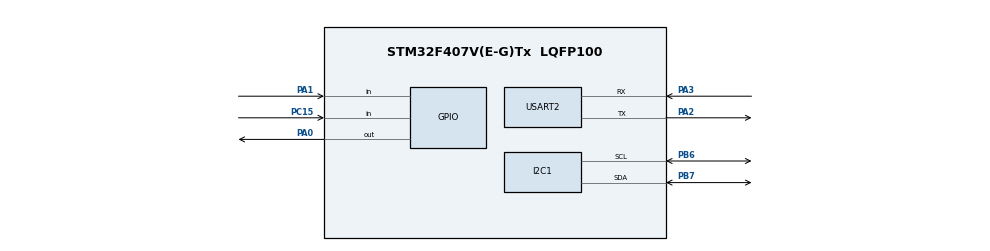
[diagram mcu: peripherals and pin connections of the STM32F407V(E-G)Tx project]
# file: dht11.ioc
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I2C1.I2C_Mode=I2C_Standard
Mcu.Family=STM32F4
Mcu.Name=STM32F407V(E-G)Tx
Mcu.Package=LQFP100
NVIC.PriorityGroup=NVIC_PRIORITYGROUP_4
PA0-WKUP.Signal=GPIO_Output
PA1.Signal=GPIO_Input
PA13.Mode=Serial_Wire
PA13.Signal=SYS_JTMS-SWDIO
PA14.Mode=Serial_Wire
PA14.Signal=SYS_JTCK-SWCLK
PA2.Mode=Asynchronous
PA2.Signal=USART2_TX
PA3.Mode=Asynchronous
PA3.Signal=USART2_RX
PB6.Mode=I2C
PB6.Signal=I2C1_SCL
PB7.Mode=I2C
PB7.Signal=I2C1_SDA
PC15-OSC32_OUT.Signal=GPIO_Input
PH0-OSC_IN.Mode=HSE-External-Oscillator
PH0-OSC_IN.Signal=RCC_OSC_IN
PH1-OSC_OUT.Mode=HSE-External-Oscillator
PH1-OSC_OUT.Signal=RCC_OSC_OUT
ProjectManager.HeapSize=0x200
ProjectManager.StackSize=0x400
ProjectManager.TargetToolchain=MDK-ARM V5.32
RCC.48MHZClocksFreq_Value=30000000
RCC.AHBFreq_Value=60000000
RCC.APB1CLKDivider=RCC_HCLK_DIV2
RCC.APB1Freq_Value=30000000
RCC.APB1TimFreq_Value=60000000
RCC.APB2CLKDivider=RCC_HCLK_DIV2
RCC.APB2Freq_Value=30000000
RCC.APB2TimFreq_Value=60000000
RCC.CortexFreq_Value=60000000
RCC.HCLKFreq_Value=60000000
RCC.HSE_VALUE=25000000
RCC.HSI_VALUE=16000000
RCC.LSE_VALUE=32768
RCC.PLLM=15
RCC.PLLN=72
RCC.PLLSourceVirtual=RCC_PLLSOURCE_HSE
RCC.SYSCLKFreq_VALUE=60000000
RCC.SYSCLKSource=RCC_SYSCLKSOURCE_PLLCLK
RCC.VCOOutputFreq_Value=120000000
TIM1.Prescaler=29
USART2.VirtualMode=VM_ASYNC
VP_TIM1_VS_ClockSourceINT.Mode=Internal
board=custom

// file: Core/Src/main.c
/* USER CODE BEGIN Header */
/**
  ******************************************************************************
  * @file           : main.c
  * @brief          : Main program body
  ******************************************************************************
  * @attention
  *
  * Copyright (c) 2025 STMicroelectronics.
  * All rights reserved.
  *
  * This software is licensed under terms that can be found in the LICENSE file
  * in the root directory of this software component.
  * If no LICENSE file comes with this software, it is provided AS-IS.
  *
  ******************************************************************************
  */
/* USER CODE END Header */
#include "main.h"

/* USER CODE BEGIN PD */
#include "dht11.h"
#include "lcd_i2c.h"
#include "stdio.h"
/* USER CODE END PD */

I2C_HandleTypeDef hi2c1;

TIM_HandleTypeDef htim1;

UART_HandleTypeDef huart2;

void SystemClock_Config(void);
static void MX_GPIO_Init(void);
static void MX_I2C1_Init(void);
static void MX_TIM1_Init(void);
static void MX_USART2_UART_Init(void);

/* USER CODE BEGIN 0 */
#define u8 uint8_t
#define u32 uint32_t
logan dht11;
void transmit_dht11(){
	u8 data[4];
	data[0] = dht11.temp1;
	data[1] = dht11.temp2;
	data[2] = dht11.hum1;
	data[3] = dht11.hum2;
	char data1[14];
	sprintf(data1, "Nhiet do: %d.%d\n", data[0], data[1]);
	HAL_UART_Transmit(&huart2, (u8*)data1, sizeof(data1), 1000);
	HAL_Delay(1500);
	char data2[11];
	sprintf(data2, "Do am: %d.%d\n", data[2], data[3]);
	HAL_UART_Transmit(&huart2, (u8*)data2, sizeof(data2), 1000);
	HAL_Delay(1500);
}

/* USER CODE END 0 */

int main(void)
{

  /* MCU Configuration--------------------------------------------------------*/

  /* Reset of all peripherals, Initializes the Flash interface and the Systick. */
  HAL_Init();

  /* Configure the system clock */
  SystemClock_Config();

  /* Initialize all configured peripherals */
  MX_GPIO_Init();
  MX_I2C1_Init();
  MX_TIM1_Init();
  MX_USART2_UART_Init();
  /* USER CODE BEGIN 2 */
	lcd_init();
  /* USER CODE END 2 */

  /* Infinite loop */
  while (1)
  {

    /* USER CODE BEGIN 3 */
		dht11_completed();
		HAL_Delay(100);
  }
  /* USER CODE END 3 */
}

void SystemClock_Config(void)
{
  RCC_OscInitTypeDef RCC_OscInitStruct = {0};
  RCC_ClkInitTypeDef RCC_ClkInitStruct = {0};

  /** Configure the main internal regulator output voltage
  */
  __HAL_RCC_PWR_CLK_ENABLE();
  __HAL_PWR_VOLTAGESCALING_CONFIG(PWR_REGULATOR_VOLTAGE_SCALE1);

  /** Initializes the RCC Oscillators according to the specified parameters
  * in the RCC_OscInitTypeDef structure.
  */
  RCC_OscInitStruct.OscillatorType = RCC_OSCILLATORTYPE_HSE;
  RCC_OscInitStruct.HSEState = RCC_HSE_ON;
  RCC_OscInitStruct.PLL.PLLState = RCC_PLL_ON;
  RCC_OscInitStruct.PLL.PLLSource = RCC_PLLSOURCE_HSE;
  RCC_OscInitStruct.PLL.PLLM = 25;
  RCC_OscInitStruct.PLL.PLLN = 128;
  RCC_OscInitStruct.PLL.PLLP = RCC_PLLP_DIV2;
  RCC_OscInitStruct.PLL.PLLQ = 4;
  if (HAL_RCC_OscConfig(&RCC_OscInitStruct) != HAL_OK)
  {
    Error_Handler();
  }

  /** Initializes the CPU, AHB and APB buses clocks
  */
  RCC_ClkInitStruct.ClockType = RCC_CLOCKTYPE_HCLK|RCC_CLOCKTYPE_SYSCLK
                              |RCC_CLOCKTYPE_PCLK1|RCC_CLOCKTYPE_PCLK2;
  RCC_ClkInitStruct.SYSCLKSource = RCC_SYSCLKSOURCE_PLLCLK;
  RCC_ClkInitStruct.AHBCLKDivider = RCC_SYSCLK_DIV8;
  RCC_ClkInitStruct.APB1CLKDivider = RCC_HCLK_DIV4;
  RCC_ClkInitStruct.APB2CLKDivider = RCC_HCLK_DIV2;

  if (HAL_RCC_ClockConfig(&RCC_ClkInitStruct, FLASH_LATENCY_0) != HAL_OK)
  {
    Error_Handler();
  }
}

static void MX_I2C1_Init(void)
{

  hi2c1.Instance = I2C1;
  hi2c1.Init.ClockSpeed = 100000;
  hi2c1.Init.DutyCycle = I2C_DUTYCYCLE_2;
  hi2c1.Init.OwnAddress1 = 0;
  hi2c1.Init.AddressingMode = I2C_ADDRESSINGMODE_7BIT;
  hi2c1.Init.DualAddressMode = I2C_DUALADDRESS_DISABLE;
  hi2c1.Init.OwnAddress2 = 0;
  hi2c1.Init.GeneralCallMode = I2C_GENERALCALL_DISABLE;
  hi2c1.Init.NoStretchMode = I2C_NOSTRETCH_DISABLE;
  if (HAL_I2C_Init(&hi2c1) != HAL_OK)
  {
    Error_Handler();
  }

}

static void MX_TIM1_Init(void)
{

  TIM_ClockConfigTypeDef sClockSourceConfig = {0};
  TIM_MasterConfigTypeDef sMasterConfig = {0};

  htim1.Instance = TIM1;
  htim1.Init.Prescaler = 9;
  htim1.Init.CounterMode = TIM_COUNTERMODE_UP;
  htim1.Init.Period = 65535;
  htim1.Init.ClockDivision = TIM_CLOCKDIVISION_DIV1;
  htim1.Init.RepetitionCounter = 0;
  htim1.Init.AutoReloadPreload = TIM_AUTORELOAD_PRELOAD_DISABLE;
  if (HAL_TIM_Base_Init(&htim1) != HAL_OK)
  {
    Error_Handler();
  }
  sClockSourceConfig.ClockSource = TIM_CLOCKSOURCE_INTERNAL;
  if (HAL_TIM_ConfigClockSource(&htim1, &sClockSourceConfig) != HAL_OK)
  {
    Error_Handler();
  }
  sMasterConfig.MasterOutputTrigger = TIM_TRGO_RESET;
  sMasterConfig.MasterSlaveMode = TIM_MASTERSLAVEMODE_DISABLE;
  if (HAL_TIMEx_MasterConfigSynchronization(&htim1, &sMasterConfig) != HAL_OK)
  {
    Error_Handler();
  }

}

static void MX_USART2_UART_Init(void)
{

  huart2.Instance = USART2;
  huart2.Init.BaudRate = 115200;
  huart2.Init.WordLength = UART_WORDLENGTH_8B;
  huart2.Init.StopBits = UART_STOPBITS_1;
  huart2.Init.Parity = UART_PARITY_NONE;
  huart2.Init.Mode = UART_MODE_TX_RX;
  huart2.Init.HwFlowCtl = UART_HWCONTROL_NONE;
  huart2.Init.OverSampling = UART_OVERSAMPLING_16;
  if (HAL_UART_Init(&huart2) != HAL_OK)
  {
    Error_Handler();
  }

}

static void MX_GPIO_Init(void)
{
  GPIO_InitTypeDef GPIO_InitStruct = {0};

  /* GPIO Ports Clock Enable */
  __HAL_RCC_GPIOC_CLK_ENABLE();
  __HAL_RCC_GPIOH_CLK_ENABLE();
  __HAL_RCC_GPIOA_CLK_ENABLE();
  __HAL_RCC_GPIOB_CLK_ENABLE();

  /*Configure GPIO pin Output Level */
  HAL_GPIO_WritePin(GPIOA, GPIO_PIN_0, GPIO_PIN_RESET);

  /*Configure GPIO pin : PC15 */
  GPIO_InitStruct.Pin = GPIO_PIN_15;
  GPIO_InitStruct.Mode = GPIO_MODE_INPUT;
  GPIO_InitStruct.Pull = GPIO_NOPULL;
  HAL_GPIO_Init(GPIOC, &GPIO_InitStruct);

  /*Configure GPIO pin : PA0 */
  GPIO_InitStruct.Pin = GPIO_PIN_0;
  GPIO_InitStruct.Mode = GPIO_MODE_OUTPUT_PP;
  GPIO_InitStruct.Pull = GPIO_NOPULL;
  GPIO_InitStruct.Speed = GPIO_SPEED_FREQ_LOW;
  HAL_GPIO_Init(GPIOA, &GPIO_InitStruct);

  /*Configure GPIO pin : PA1 */
  GPIO_InitStruct.Pin = GPIO_PIN_1;
  GPIO_InitStruct.Mode = GPIO_MODE_INPUT;
  GPIO_InitStruct.Pull = GPIO_NOPULL;
  HAL_GPIO_Init(GPIOA, &GPIO_InitStruct);

}

void Error_Handler(void)
{
  __disable_irq();
  while (1)
  {
  }
}
